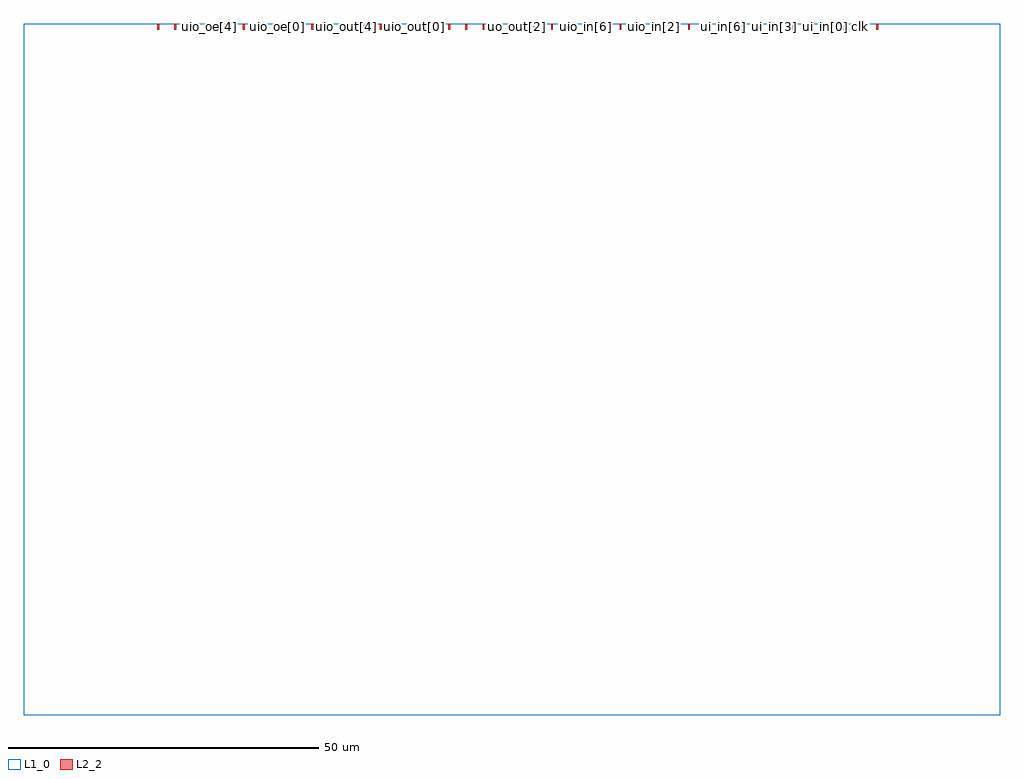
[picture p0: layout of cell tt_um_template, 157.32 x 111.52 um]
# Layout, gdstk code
import gdstk
lib = gdstk.Library(unit=1e-6, precision=1e-09)
def R(c, l, rs):  # rectangles x0, y0, x1, y1
    for r in rs: c.add(gdstk.rectangle(r[:2], r[2:], *l))
def A(c, l, x, y, w, h, nx, ny, dx, dy):  # array of equal rectangles
    R(c, l, [(x+i*dx, y+j*dy, x+i*dx+w, y+j*dy+h) for i in range(nx) for j in range(ny)])
L1_0 = (1, 0)
L2_2 = (2, 2)

tt_um_template = lib.new_cell('tt_um_template')
R(tt_um_template, L1_0, [(0,0,157.32,111.52)])
A(tt_um_template, L2_2, 21.47, 110.52, 0.3, 1, 43, 1, 2.76, 0)
tt_um_template.add(gdstk.Label('clk', (134.78,111.02), layer=2, texttype=1))
tt_um_template.add(gdstk.Label('ena', (137.54,111.02), layer=2, texttype=1))
tt_um_template.add(gdstk.Label('rst_n', (132.02,111.02), layer=2, texttype=1))
tt_um_template.add(gdstk.Label('ui_in[0]', (129.26,111.02), layer=2, texttype=1))
tt_um_template.add(gdstk.Label('ui_in[1]', (126.5,111.02), layer=2, texttype=1))
tt_um_template.add(gdstk.Label('ui_in[2]', (123.74,111.02), layer=2, texttype=1))
tt_um_template.add(gdstk.Label('ui_in[3]', (120.98,111.02), layer=2, texttype=1))
tt_um_template.add(gdstk.Label('ui_in[4]', (118.22,111.02), layer=2, texttype=1))
tt_um_template.add(gdstk.Label('ui_in[5]', (115.46,111.02), layer=2, texttype=1))
tt_um_template.add(gdstk.Label('ui_in[6]', (112.7,111.02), layer=2, texttype=1))
tt_um_template.add(gdstk.Label('ui_in[7]', (109.94,111.02), layer=2, texttype=1))
tt_um_template.add(gdstk.Label('uio_in[0]', (107.18,111.02), layer=2, texttype=1))
tt_um_template.add(gdstk.Label('uio_in[1]', (104.42,111.02), layer=2, texttype=1))
tt_um_template.add(gdstk.Label('uio_in[2]', (101.66,111.02), layer=2, texttype=1))
tt_um_template.add(gdstk.Label('uio_in[3]', (98.9,111.02), layer=2, texttype=1))
tt_um_template.add(gdstk.Label('uio_in[4]', (96.14,111.02), layer=2, texttype=1))
tt_um_template.add(gdstk.Label('uio_in[5]', (93.38,111.02), layer=2, texttype=1))
tt_um_template.add(gdstk.Label('uio_in[6]', (90.62,111.02), layer=2, texttype=1))
tt_um_template.add(gdstk.Label('uio_in[7]', (87.86,111.02), layer=2, texttype=1))
tt_um_template.add(gdstk.Label('uio_oe[0]', (40.94,111.02), layer=2, texttype=1))
tt_um_template.add(gdstk.Label('uio_oe[1]', (38.18,111.02), layer=2, texttype=1))
tt_um_template.add(gdstk.Label('uio_oe[2]', (35.42,111.02), layer=2, texttype=1))
tt_um_template.add(gdstk.Label('uio_oe[3]', (32.66,111.02), layer=2, texttype=1))
tt_um_template.add(gdstk.Label('uio_oe[4]', (29.9,111.02), layer=2, texttype=1))
tt_um_template.add(gdstk.Label('uio_oe[5]', (27.14,111.02), layer=2, texttype=1))
tt_um_template.add(gdstk.Label('uio_oe[6]', (24.38,111.02), layer=2, texttype=1))
tt_um_template.add(gdstk.Label('uio_oe[7]', (21.62,111.02), layer=2, texttype=1))
tt_um_template.add(gdstk.Label('uio_out[0]', (63.02,111.02), layer=2, texttype=1))
tt_um_template.add(gdstk.Label('uio_out[1]', (60.26,111.02), layer=2, texttype=1))
tt_um_template.add(gdstk.Label('uio_out[2]', (57.5,111.02), layer=2, texttype=1))
tt_um_template.add(gdstk.Label('uio_out[3]', (54.74,111.02), layer=2, texttype=1))
tt_um_template.add(gdstk.Label('uio_out[4]', (51.98,111.02), layer=2, texttype=1))
tt_um_template.add(gdstk.Label('uio_out[5]', (49.22,111.02), layer=2, texttype=1))
tt_um_template.add(gdstk.Label('uio_out[6]', (46.46,111.02), layer=2, texttype=1))
tt_um_template.add(gdstk.Label('uio_out[7]', (43.7,111.02), layer=2, texttype=1))
tt_um_template.add(gdstk.Label('uo_out[0]', (85.1,111.02), layer=2, texttype=1))
tt_um_template.add(gdstk.Label('uo_out[1]', (82.34,111.02), layer=2, texttype=1))
tt_um_template.add(gdstk.Label('uo_out[2]', (79.58,111.02), layer=2, texttype=1))
tt_um_template.add(gdstk.Label('uo_out[3]', (76.82,111.02), layer=2, texttype=1))
tt_um_template.add(gdstk.Label('uo_out[4]', (74.06,111.02), layer=2, texttype=1))
tt_um_template.add(gdstk.Label('uo_out[5]', (71.3,111.02), layer=2, texttype=1))
tt_um_template.add(gdstk.Label('uo_out[6]', (68.54,111.02), layer=2, texttype=1))
tt_um_template.add(gdstk.Label('uo_out[7]', (65.78,111.02), layer=2, texttype=1))

lib.write_gds('tt_um_template.gds')
